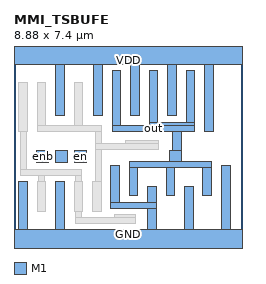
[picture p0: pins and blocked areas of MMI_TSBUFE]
MACRO MMI_TSBUFE
	CLASS CORE ;
	FOREIGN MMI_TSBUFE 0 0 ;
	SIZE 8.88 BY 7.4 ;
	SYMMETRY X Y ;
	SITE CORE1 ;
	PIN out
		DIRECTION output ;
		USE SIGNAL ;
		PORT
			LAYER M1 ;
			RECT 3.82 4.525 4.16 6.67 ;
			LAYER M1 ;
			RECT 5.26 4.65 5.6 6.67 ;
			LAYER M1 ;
			RECT 6.7 4.65 7.04 6.67 ;
			LAYER M1 ;
			RECT 5.26 4.525 7.04 4.65 ;
			LAYER M1 ;
			RECT 3.82 4.295 7.04 4.525 ;
			LAYER M1 ;
			RECT 6.17 3.555 6.51 4.295 ;
			LAYER M1 ;
			RECT 6.065 3.135 6.515 3.555 ;
			LAYER M1 ;
			RECT 4.48 2.905 7.7 3.135 ;
			LAYER M1 ;
			RECT 4.48 1.82 4.82 2.905 ;
			LAYER M1 ;
			RECT 5.92 1.82 6.26 2.905 ;
			LAYER M1 ;
			RECT 7.36 1.82 7.7 2.905 ;
		END
		AntennaDiffArea 5.9616 ;
	END out
	PIN GND
		DIRECTION inout ;
		USE GROUND ;
		PORT
			LAYER M1 ;
			RECT 0.18 0.5 0.52 2.36 ;
			LAYER M1 ;
			RECT 1.62 0.5 1.96 2.36 ;
			LAYER M1 ;
			RECT 3.76 1.55 4.1 2.965 ;
			LAYER M1 ;
			RECT 5.2 1.55 5.54 2.16 ;
			LAYER M1 ;
			RECT 3.76 1.32 5.54 1.55 ;
			LAYER M1 ;
			RECT 5.2 0.5 5.54 1.32 ;
			LAYER M1 ;
			RECT 6.64 0.5 6.98 2.16 ;
			LAYER M1 ;
			RECT 8.08 0.5 8.42 2.965 ;
			LAYER M1 ;
			RECT 0 -0.5 8.88 0.5 ;
		END
	END GND
	PIN enb
		DIRECTION input ;
		USE SIGNAL ;
		PORT
			LAYER M1 ;
			RECT 0.885 3.105 1.335 3.555 ;
		END
		AntennaGateArea 0.5832 ;
	END enb
	PIN VDD
		DIRECTION inout ;
		USE POWER ;
		PORT
			LAYER M1 ;
			RECT 0 6.9 8.88 7.9 ;
			LAYER M1 ;
			RECT 1.62 4.935 1.96 6.9 ;
			LAYER M1 ;
			RECT 3.1 4.915 3.44 6.9 ;
			LAYER M1 ;
			RECT 4.54 4.915 4.88 6.9 ;
			LAYER M1 ;
			RECT 5.98 4.915 6.32 6.9 ;
			LAYER M1 ;
			RECT 7.42 4.295 7.76 6.9 ;
		END
	END VDD
	PIN en
		DIRECTION input ;
		USE SIGNAL ;
		PORT
			LAYER M1 ;
			RECT 2.365 3.105 2.815 3.555 ;
		END
		AntennaGateArea 0.5832 ;
	END en
	PIN in
		DIRECTION input ;
		USE SIGNAL ;
		PORT
			LAYER M1 ;
			RECT 1.625 3.105 2.075 3.555 ;
		END
		AntennaGateArea 1.1664 ;
	END in
	OBS
		LAYER M1 ;
		RECT 0.18 4.295 0.52 6.215 ;
		LAYER M1 ;
		RECT 0.9 4.525 1.24 6.215 ;
		LAYER M1 ;
		RECT 2.34 4.525 2.68 6.215 ;
		LAYER M1 ;
		RECT 0.9 4.295 3.4 4.525 ;
		LAYER M1 ;
		RECT 0.24 2.825 0.47 4.295 ;
		LAYER M1 ;
		RECT 3.17 3.825 3.4 4.295 ;
		LAYER M1 ;
		RECT 4.355 3.825 5.635 3.935 ;
		LAYER M1 ;
		RECT 3.17 3.595 5.635 3.825 ;
		LAYER M1 ;
		RECT 0.24 2.595 2.62 2.825 ;
		LAYER M1 ;
		RECT 0.95 2.36 1.18 2.595 ;
		LAYER M1 ;
		RECT 2.39 2.36 2.62 2.595 ;
		LAYER M1 ;
		RECT 3.17 2.36 3.4 3.595 ;
		LAYER M1 ;
		RECT 0.9 1.2 1.24 2.36 ;
		LAYER M1 ;
		RECT 2.34 1.2 2.68 2.36 ;
		LAYER M1 ;
		RECT 3.06 1.2 3.4 2.36 ;
		LAYER M1 ;
		RECT 2.4 0.97 2.63 1.2 ;
		LAYER M1 ;
		RECT 3.925 0.97 4.735 1.075 ;
		LAYER M1 ;
		RECT 2.4 0.74 4.735 0.97 ;
		LAYER M1 ;
		RECT 3.925 0.735 4.735 0.74 ;
	END
END MMI_TSBUFE
